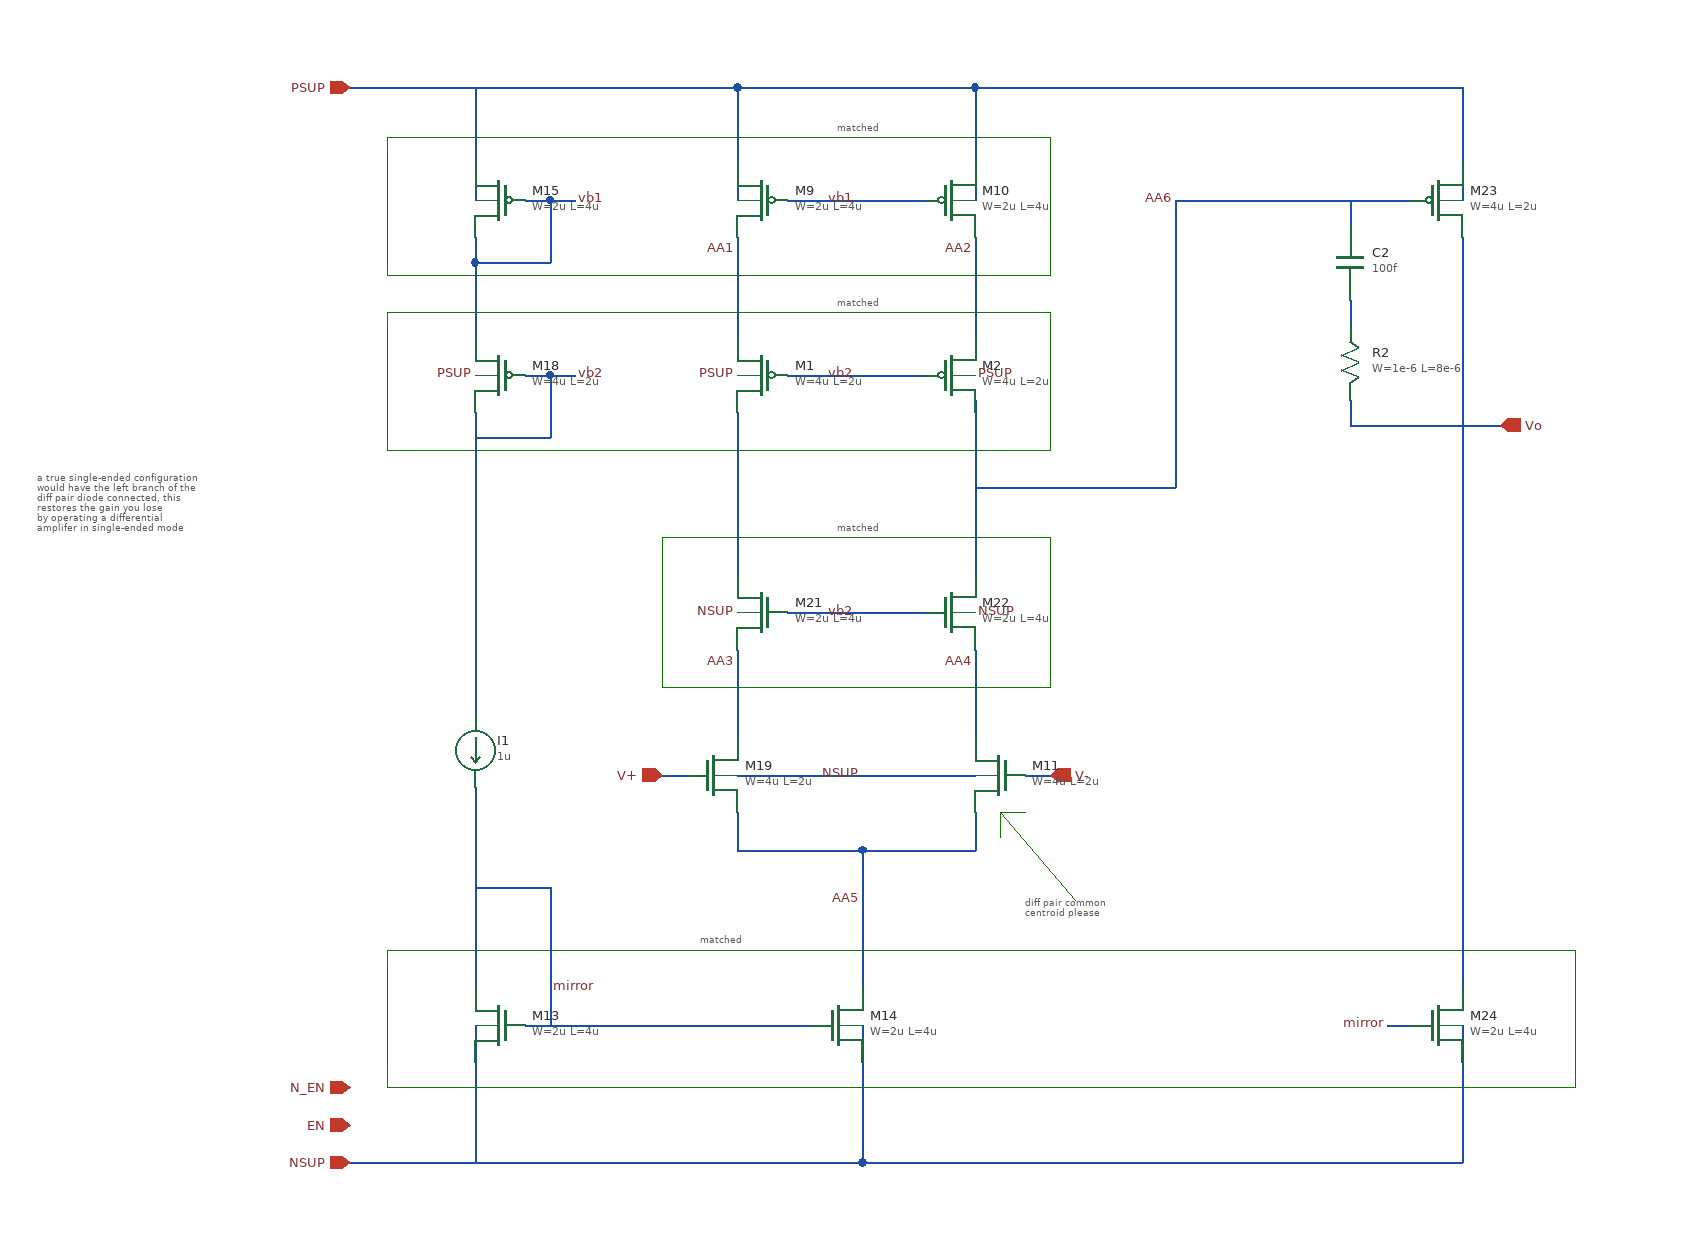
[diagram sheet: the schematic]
v {xschem version=3.4.7 file_version=1.2}
G {}
K {}
V {}
S {}
E {}
L 4 600 -310 1130 -310 {}
L 4 600 -420 600 -310 {}
L 4 600 -420 1130 -420 {}
L 4 1130 -420 1130 -310 {}
L 4 600 340 1550 340 {}
L 4 600 230 600 340 {}
L 4 600 230 1550 230 {}
L 4 1550 230 1550 340 {}
L 4 1090 120 1090 140 {}
L 4 1090 120 1110 120 {}
L 4 1090 120 1150 190 {}
L 4 600 -280 600 -170 {}
L 4 600 -280 1130 -280 {}
L 4 1130 -280 1130 -170 {}
L 4 600 -170 1130 -170 {}
L 4 820 -100 1130 -100 {}
L 4 1130 -100 1130 20 {}
L 4 820 20 1130 20 {}
L 4 820 -100 820 20 {}
T {diff pair common 
centroid please} 1110 180 0 0 0.2 0.2 {}
T {matched} 850 210 0 0 0.2 0.2 {}
T {matched} 960 -440 0 0 0.2 0.2 {}
T {matched} 960 -300 0 0 0.2 0.2 {}
T {matched} 960 -120 0 0 0.2 0.2 {}
T {a true single-ended configuration
would have the left branch of the 
diff pair diode connected, this 
restores the gain you lose
by operating a differential 
amplifer in single-ended mode} 320 -160 0 0 0.2 0.2 {}
N 980 150 1070 150 {lab=AA5}
N 800 -460 880 -460 {lab=PSUP}
N 730 400 980 400 {lab=NSUP}
N 880 120 880 150 {lab=AA5}
N 1070 120 1070 150 {lab=AA5}
N 1110 90 1130 90 {lab=V-}
N 820 90 840 90 {lab=V+}
N 880 -460 880 -370 {lab=PSUP}
N 880 -460 1070 -460 {lab=PSUP}
N 1070 -460 1070 -370 {lab=PSUP}
N 880 90 1070 90 {lab=NSUP}
N 880 150 980 150 {lab=AA5}
N 920 -370 940 -370 {lab=vb1}
N 1070 -210 1070 -70 {lab=AA6}
N 570 -460 770 -460 {lab=PSUP}
N 570 400 700 400 {lab=NSUP}
N 740 290 940 290 {lab=mirror}
N 980 320 980 380 {lab=NSUP}
N 980 380 980 400 {lab=NSUP}
N 670 290 670 400 {lab=NSUP}
N 730 240 730 290 {lab=mirror}
N 670 180 730 180 {lab=mirror}
N 670 240 670 260 {lab=mirror}
N 670 210 670 240 {lab=mirror}
N 980 290 980 320 {lab=NSUP}
N 670 100 670 210 {lab=mirror}
N 730 180 730 240 {lab=mirror}
N 980 150 980 260 {lab=AA5}
N 940 -370 1030 -370 {lab=vb1}
N 730 -370 750 -370 {lab=vb1}
N 670 -460 670 -370 {lab=PSUP}
N 710 -370 730 -370 {lab=vb1}
N 730 -370 730 -320 {lab=vb1}
N 670 -340 670 -320 {lab=vb1}
N 670 -320 730 -320 {lab=vb1}
N 700 400 730 400 {lab=NSUP}
N 710 290 740 290 {lab=mirror}
N 770 -460 800 -460 {lab=PSUP}
N 920 -230 940 -230 {lab=vb2}
N 940 -230 1030 -230 {lab=vb2}
N 730 -230 750 -230 {lab=vb2}
N 710 -230 730 -230 {lab=vb2}
N 730 -230 730 -180 {lab=vb2}
N 880 -340 880 -320 {lab=AA1}
N 880 -200 880 -190 {lab=#net1}
N 670 -200 670 -150 {lab=vb2}
N 880 -190 880 -70 {lab=#net1}
N 920 -40 940 -40 {lab=vb2}
N 940 -40 1030 -40 {lab=vb2}
N 880 -10 880 0 {lab=AA3}
N 670 -10 670 40 {lab=vb2}
N 880 0 880 50 {lab=AA3}
N 1070 40 1070 60 {lab=AA4}
N 880 50 880 60 {lab=AA3}
N 670 -90 670 -70 {lab=vb2}
N 670 -150 670 -90 {lab=vb2}
N 670 -180 730 -180 {lab=vb2}
N 1460 320 1460 380 {lab=NSUP}
N 1460 290 1460 320 {lab=NSUP}
N 1400 290 1420 290 {lab=mirror}
N 1100 400 1410 400 {lab=NSUP}
N 1460 380 1460 400 {lab=NSUP}
N 1410 400 1460 400 {lab=NSUP}
N 1460 -460 1460 -400 {lab=PSUP}
N 1460 -400 1460 -370 {lab=PSUP}
N 1460 -50 1460 260 {lab=Vo}
N 1460 -340 1460 -330 {lab=Vo}
N 1460 -190 1490 -190 {lab=Vo}
N 1320 -370 1390 -370 {lab=AA6}
N 1370 -290 1370 -270 {lab=#net2}
N 1370 -370 1370 -350 {lab=AA6}
N 1370 -210 1370 -190 {lab=Vo}
N 1400 -190 1460 -190 {lab=Vo}
N 1370 -190 1400 -190 {lab=Vo}
N 1390 -370 1420 -370 {lab=AA6}
N 980 400 1100 400 {lab=NSUP}
N 1070 -460 1460 -460 {lab=PSUP}
N 1460 -330 1460 -50 {lab=Vo}
N 1230 -370 1320 -370 {lab=AA6}
N 1230 -370 1230 -140 {lab=AA6}
N 1070 -140 1230 -140 {lab=AA6}
N 670 -70 670 -10 {lab=vb2}
N 670 -320 670 -260 {lab=vb1}
N 1070 -10 1070 40 {lab=AA4}
N 1070 -340 1070 -260 {lab=AA2}
N 880 -320 880 -260 {lab=AA1}
C {symbols/pfet_06v0.sym} 900 -370 0 1 {name=M9
L=4u
W=2u
nf=2
m=2
ad="'int((nf+1)/2) * W/nf * 0.18u'"
pd="'2*int((nf+1)/2) * (W/nf + 0.18u)'"
as="'int((nf+2)/2) * W/nf * 0.18u'"
ps="'2*int((nf+2)/2) * (W/nf + 0.18u)'"
nrd="'0.18u / W'" nrs="'0.18u / W'"
sa=0 sb=0 sd=0
model=pfet_06v0
spiceprefix=X
}
C {symbols/pfet_06v0.sym} 1050 -370 0 0 {name=M10
L=4u
W=2u
nf=2
m=2
ad="'int((nf+1)/2) * W/nf * 0.18u'"
pd="'2*int((nf+1)/2) * (W/nf + 0.18u)'"
as="'int((nf+2)/2) * W/nf * 0.18u'"
ps="'2*int((nf+2)/2) * (W/nf + 0.18u)'"
nrd="'0.18u / W'" nrs="'0.18u / W'"
sa=0 sb=0 sd=0
model=pfet_06v0
spiceprefix=X
}
C {noconn.sym} 570 340 0 1 {name=l3}
C {noconn.sym} 570 370 0 1 {name=l4}
C {ipin.sym} 570 -460 0 0 {name=p16 lab=PSUP
}
C {ipin.sym} 570 400 0 0 {name=p17 lab=NSUP
}
C {ipin.sym} 570 340 0 0 {name=p18 lab=N_EN

}
C {ipin.sym} 570 370 0 0 {name=p19 lab=EN
}
C {ipin.sym} 820 90 0 0 {name=p20 lab=V+

}
C {ipin.sym} 1130 90 0 1 {name=p21 lab=V-

}
C {lab_pin.sym} 980 90 0 0 {name=p23 sig_type=std_logic lab=NSUP}
C {symbols/nfet_06v0_nvt.sym} 1090 90 0 1 {name=M11
L=2u
W=4u
nf=5
m=4
ad="'int((nf+1)/2) * W/nf * 0.18u'"
pd="'2*int((nf+1)/2) * (W/nf + 0.18u)'"
as="'int((nf+2)/2) * W/nf * 0.18u'"
ps="'2*int((nf+2)/2) * (W/nf + 0.18u)'"
nrd="'0.18u / W'" nrs="'0.18u / W'"
sa=0 sb=0 sd=0
model=nfet_06v0
spiceprefix=X
}
C {lab_pin.sym} 880 -330 0 0 {name=p24 sig_type=std_logic lab=AA1}
C {symbols/nfet_06v0_nvt.sym} 690 290 0 1 {name=M13
L=4u
W=2u
nf=2
m=1
ad="'int((nf+1)/2) * W/nf * 0.18u'"
pd="'2*int((nf+1)/2) * (W/nf + 0.18u)'"
as="'int((nf+2)/2) * W/nf * 0.18u'"
ps="'2*int((nf+2)/2) * (W/nf + 0.18u)'"
nrd="'0.18u / W'" nrs="'0.18u / W'"
sa=0 sb=0 sd=0
model=nfet_06v0
spiceprefix=X
}
C {lab_pin.sym} 730 260 2 0 {name=p25 sig_type=std_logic lab=mirror
}
C {isource.sym} 670 70 0 0 {name=I1 value=1u
}
C {symbols/nfet_06v0_nvt.sym} 960 290 0 0 {name=M14
L=4u
W=2u
nf=2
m=2
ad="'int((nf+1)/2) * W/nf * 0.18u'"
pd="'2*int((nf+1)/2) * (W/nf + 0.18u)'"
as="'int((nf+2)/2) * W/nf * 0.18u'"
ps="'2*int((nf+2)/2) * (W/nf + 0.18u)'"
nrd="'0.18u / W'" nrs="'0.18u / W'"
sa=0 sb=0 sd=0
model=nfet_06v0
spiceprefix=X
}
C {lab_pin.sym} 950 -370 2 0 {name=p26 sig_type=std_logic lab=vb1
}
C {lab_pin.sym} 750 -370 0 1 {name=p27 sig_type=std_logic lab=vb1
}
C {symbols/pfet_06v0.sym} 690 -370 0 1 {name=M15
L=4u
W=2u
nf=2
m=1
ad="'int((nf+1)/2) * W/nf * 0.18u'"
pd="'2*int((nf+1)/2) * (W/nf + 0.18u)'"
as="'int((nf+2)/2) * W/nf * 0.18u'"
ps="'2*int((nf+2)/2) * (W/nf + 0.18u)'"
nrd="'0.18u / W'" nrs="'0.18u / W'"
sa=0 sb=0 sd=0
model=pfet_06v0
spiceprefix=X
}
C {lab_pin.sym} 950 -230 2 0 {name=p28 sig_type=std_logic lab=vb2
}
C {lab_pin.sym} 750 -230 0 1 {name=p29 sig_type=std_logic lab=vb2}
C {symbols/pfet_06v0.sym} 690 -230 0 1 {name=M18
L=2u
W=4u
nf=2
m=1
ad="'int((nf+1)/2) * W/nf * 0.18u'"
pd="'2*int((nf+1)/2) * (W/nf + 0.18u)'"
as="'int((nf+2)/2) * W/nf * 0.18u'"
ps="'2*int((nf+2)/2) * (W/nf + 0.18u)'"
nrd="'0.18u / W'" nrs="'0.18u / W'"
sa=0 sb=0 sd=0
model=pfet_06v0
spiceprefix=X
}
C {lab_pin.sym} 1070 -330 0 0 {name=p30 sig_type=std_logic lab=AA2}
C {lab_pin.sym} 880 0 0 0 {name=p31 sig_type=std_logic lab=AA3}
C {lab_pin.sym} 950 -40 2 0 {name=p32 sig_type=std_logic lab=vb2}
C {lab_pin.sym} 1070 0 0 0 {name=p33 sig_type=std_logic lab=AA4}
C {symbols/nfet_06v0_nvt.sym} 860 90 0 0 {name=M19
L=2u
W=4u
nf=5
m=4
ad="'int((nf+1)/2) * W/nf * 0.18u'"
pd="'2*int((nf+1)/2) * (W/nf + 0.18u)'"
as="'int((nf+2)/2) * W/nf * 0.18u'"
ps="'2*int((nf+2)/2) * (W/nf + 0.18u)'"
nrd="'0.18u / W'" nrs="'0.18u / W'"
sa=0 sb=0 sd=0
model=nfet_06v0
spiceprefix=X
}
C {symbols/nfet_06v0_nvt.sym} 900 -40 0 1 {name=M21
L=4u
W=2u
nf=2
m=2
ad="'int((nf+1)/2) * W/nf * 0.18u'"
pd="'2*int((nf+1)/2) * (W/nf + 0.18u)'"
as="'int((nf+2)/2) * W/nf * 0.18u'"
ps="'2*int((nf+2)/2) * (W/nf + 0.18u)'"
nrd="'0.18u / W'" nrs="'0.18u / W'"
sa=0 sb=0 sd=0
model=nfet_06v0
spiceprefix=X
}
C {symbols/nfet_06v0_nvt.sym} 1050 -40 0 0 {name=M22
L=4u
W=2u
nf=2
m=2
ad="'int((nf+1)/2) * W/nf * 0.18u'"
pd="'2*int((nf+1)/2) * (W/nf + 0.18u)'"
as="'int((nf+2)/2) * W/nf * 0.18u'"
ps="'2*int((nf+2)/2) * (W/nf + 0.18u)'"
nrd="'0.18u / W'" nrs="'0.18u / W'"
sa=0 sb=0 sd=0
model=nfet_06v0
spiceprefix=X
}
C {lab_pin.sym} 980 190 0 0 {name=p37 sig_type=std_logic lab=AA5}
C {opin.sym} 1490 -190 0 0 {name=p39 lab=Vo}
C {capa.sym} 1370 -320 2 0 {name=C2
m=1
value=100f
footprint=1206
device="ceramic capacitor"
}
C {lab_pin.sym} 1400 290 0 0 {name=p40 sig_type=std_logic lab=mirror
}
C {symbols/pfet_06v0.sym} 1440 -370 0 0 {name=M23
L=2u
W=4u
nf=4
m=8
ad="'int((nf+1)/2) * W/nf * 0.18u'"
pd="'2*int((nf+1)/2) * (W/nf + 0.18u)'"
as="'int((nf+2)/2) * W/nf * 0.18u'"
ps="'2*int((nf+2)/2) * (W/nf + 0.18u)'"
nrd="'0.18u / W'" nrs="'0.18u / W'"
sa=0 sb=0 sd=0
model=pfet_06v0
spiceprefix=X
}
C {symbols/nfet_06v0_nvt.sym} 1440 290 0 0 {name=M24
L=4u
W=2u
nf=4
m=4
ad="'int((nf+1)/2) * W/nf * 0.18u'"
pd="'2*int((nf+1)/2) * (W/nf + 0.18u)'"
as="'int((nf+2)/2) * W/nf * 0.18u'"
ps="'2*int((nf+2)/2) * (W/nf + 0.18u)'"
nrd="'0.18u / W'" nrs="'0.18u / W'"
sa=0 sb=0 sd=0
model=nfet_06v0
spiceprefix=X
}
C {symbols/ppolyf_u_3k.sym} 1370 -240 2 1 {name=R2
W=1e-6
L=8e-6
model=ppolyf_u_3k
spiceprefix=X
m=1}
C {symbols/pfet_06v0.sym} 900 -230 0 1 {name=M1
L=2u
W=4u
nf=2
m=2
ad="'int((nf+1)/2) * W/nf * 0.18u'"
pd="'2*int((nf+1)/2) * (W/nf + 0.18u)'"
as="'int((nf+2)/2) * W/nf * 0.18u'"
ps="'2*int((nf+2)/2) * (W/nf + 0.18u)'"
nrd="'0.18u / W'" nrs="'0.18u / W'"
sa=0 sb=0 sd=0
model=pfet_06v0
spiceprefix=X
}
C {symbols/pfet_06v0.sym} 1050 -230 0 0 {name=M2
L=2u
W=4u
nf=2
m=2
ad="'int((nf+1)/2) * W/nf * 0.18u'"
pd="'2*int((nf+1)/2) * (W/nf + 0.18u)'"
as="'int((nf+2)/2) * W/nf * 0.18u'"
ps="'2*int((nf+2)/2) * (W/nf + 0.18u)'"
nrd="'0.18u / W'" nrs="'0.18u / W'"
sa=0 sb=0 sd=0
model=pfet_06v0
spiceprefix=X
}
C {lab_pin.sym} 1230 -370 0 0 {name=p1 sig_type=std_logic lab=AA6}
C {lab_pin.sym} 670 -230 0 0 {name=p2 sig_type=std_logic lab=PSUP}
C {lab_pin.sym} 1070 -40 0 1 {name=p4 sig_type=std_logic lab=NSUP}
C {lab_pin.sym} 880 -40 0 0 {name=p5 sig_type=std_logic lab=NSUP}
C {lab_pin.sym} 880 -230 0 0 {name=p6 sig_type=std_logic lab=PSUP}
C {lab_pin.sym} 1070 -230 0 1 {name=p7 sig_type=std_logic lab=PSUP}
